VERSION 5.7 ;
BUSBITCHARS "[]" ;
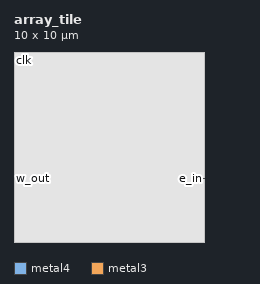
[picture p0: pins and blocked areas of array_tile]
MACRO array_tile
  FOREIGN array_tile 0 0 ;
  SYMMETRY X Y R90 ;
  SIZE 10 BY 10 ;
  CLASS BLOCK ;
  PIN clk
    DIRECTION INPUT ;
    USE SIGNAL ;
    PORT
      LAYER metal4 ;
      RECT 0.000 9.9995 0.0005 10.00 ;
    END
  END clk
  PIN e_in
    DIRECTION INPUT ;
    USE SIGNAL ;
    PORT
      LAYER metal3 ;
      RECT 9.9975 3.3335 10.00 3.3355 ;
    END
  END e_in
  PIN e_out
    DIRECTION OUTPUT ;
    USE SIGNAL ;
    PORT
      LAYER metal3 ;
      RECT 9.9975 3.338 10.00 3.3405 ;
    END
  END e_out
  PIN w_in
    DIRECTION INPUT ;
    USE SIGNAL ;
    PORT
      LAYER metal3 ;
      RECT 0.000 3.338 0.0025 3.3405 ;
    END
  END w_in
  PIN w_out
    DIRECTION OUTPUT ;
    USE SIGNAL ;
    PORT
      LAYER metal3 ;
      RECT 0.000 3.3335 0.0025 3.3355 ;
    END
  END w_out
  OBS
    LAYER metal1 ;
    RECT 0 0 10 10 ;
    LAYER metal2 ;
    RECT 0 0 10 10 ;
    LAYER metal3 ;
    RECT 0 0 10 10 ;
    LAYER metal4 ;
    RECT 0 0 10 10 ;
    LAYER metal5 ;
    RECT 0 0 10 10 ;
    LAYER OVERLAP ;
    RECT 0 0 10 10 ;
  END
END array_tile

END LIBRARY
